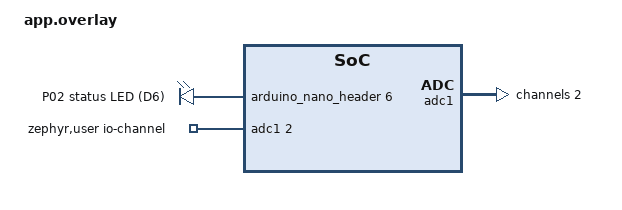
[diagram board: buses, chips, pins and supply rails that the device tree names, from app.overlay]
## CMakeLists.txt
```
# P02 on Zephyr – the Arduino Nano ESP32.

cmake_minimum_required(VERSION 3.20.0)

# Our board definition lives in this repository (zephyr/boards/arduino/nano_esp32).
list(APPEND BOARD_ROOT ${CMAKE_CURRENT_SOURCE_DIR}/..)

find_package(Zephyr REQUIRED HINTS $ENV{ZEPHYR_BASE})
project(p02_zephyr)

# P02's shared code: interfaces, stubs and drivers live in main/ (shared with the ESP-IDF build).
set(P02_MAIN ${CMAKE_CURRENT_SOURCE_DIR}/../../main)
target_include_directories(app PRIVATE ${P02_MAIN}/include)

target_sources(app PRIVATE
    src/main.cpp
    ${P02_MAIN}/source/driver/timer/zephyr.cpp
    ${P02_MAIN}/source/driver/gpio/zephyr.cpp
    ${P02_MAIN}/source/driver/adc/zephyr.cpp
    ${P02_MAIN}/source/driver/serial/zephyr.cpp
    ${P02_MAIN}/source/driver/tempsensor/tmp36.cpp
    ${P02_MAIN}/source/driver/factory/zephyr.cpp
    ${P02_MAIN}/source/driver/nvs/zephyr.cpp
    ${P02_MAIN}/source/driver/watchdog/zephyr.cpp
    ${P02_MAIN}/source/logic/logic.cpp
)
```

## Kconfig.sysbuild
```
# Sysbuild settings for P02 that depend on the board. Settings for every board are in sysbuild.conf.
#
# A Kconfig.sysbuild in the app directory replaces sysbuild's Kconfig root, so the file ends by sourcing
# it. The defaults below come first on purpose: Kconfig uses the first default of a choice whose condition
# is true, and Zephyr's own defaults (swap using offset; overwrite only on Espressif chips) are in the
# sourced files.

# The MCUboot mode: one that can roll an update back. Swap using move works with equal slots, as on these
# boards. The Daisy Seed is not listed: its board keeps RAM load (zephyr/boards/electrosmith/daisy_seed/
# Kconfig.sysbuild).
choice MCUBOOT_MODE
	default MCUBOOT_MODE_SWAP_USING_MOVE if BOARD_NUCLEO_G0B1RE
	default MCUBOOT_MODE_SWAP_USING_MOVE if BOARD_ARDUINO_NANO_ESP32
endchoice

source "share/sysbuild/Kconfig"
```

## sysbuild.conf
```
# P02 on Zephyr boots through MCUboot on every board (build with --sysbuild).
# No signature yet, only a hash check; this also overrides the Daisy board's own default.
# The MCUboot mode is left to each board: setting it here would override the Daisy's RAM load
# (see AGENTS.md: Bootloader).
SB_CONFIG_BOOTLOADER_MCUBOOT=y
SB_CONFIG_BOOT_SIGNATURE_TYPE_NONE=y
```

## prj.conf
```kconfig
# C++17 with the full standard library
CONFIG_CPP=y
CONFIG_STD_CPP17=y
CONFIG_REQUIRES_FULL_LIBCPP=y

# Wait 1 s before booting, so the monitor can open the USB console (re-attached by usbipd after the
# reset) before the boot output is printed.
CONFIG_BOOT_DELAY=1000

# std::this_thread::sleep_for in Logic::step() needs POSIX functions from libstdc++ (usleep, sleep,
# gettimeofday); without this the link fails.
CONFIG_POSIX_API=y

# Logic runs in the main thread, including `store` (Settings -> NVS -> flash driver). Zephyr's default
# of 1 KB is too small for that (see AGENTS.md: Main stack).
CONFIG_MAIN_STACK_SIZE=4096

CONFIG_ADC=y

# serial::Zephyr reads DTR to see when a monitor opens the port, and then drops the input received
# before (on a USB serial port, CDC ACM; other UARTs report "not supported" and nothing changes).
CONFIG_UART_LINE_CTRL=y

# serial::Zephyr receives by interrupt into a ring buffer, so bytes arriving between two readLine()
# calls are kept.
CONFIG_UART_INTERRUPT_DRIVEN=y
CONFIG_RING_BUFFER=y

# nvs::Zephyr: the Settings subsystem stores its keys in storage_partition with the NVS backend.
CONFIG_FLASH=y
CONFIG_FLASH_MAP=y
CONFIG_NVS=y
CONFIG_SETTINGS=y

# Watchdog (driver::watchdog::Zephyr) and the reset cause (hwinfo) for causedLastReset().
CONFIG_WATCHDOG=y
CONFIG_HWINFO=y
```

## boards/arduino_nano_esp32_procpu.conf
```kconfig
# Turns the interrupt API off, so serial::Zephyr polls with uart_poll_in(): receive by interrupt
# does not work on the Nano's USB-Serial/JTAG.
CONFIG_UART_INTERRUPT_DRIVEN=n
```

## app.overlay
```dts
/*
 * P02 wiring on the breadboard for the Zephyr app.
 *
 * Status LED on D6 (GPIO9): D6 -> 330 ohm -> LED anode, LED cathode -> GND.
 * The pin drives the LED directly, so it is active high.
 *
 * TMP36 temperature sensor on A6 (GPIO13 = ADC2 channel 2): Vout -> A6, Vs -> 3V3, GND -> GND.
 * Note: ADC2 cannot be used while Wi-Fi is active - move the TMP36 to A0-A3 (ADC1) when Wi-Fi
 * is added.
 *
 * Only P02's own wiring belongs here. The LEDs on the board itself (led0-led3) are defined by the
 * board (zephyr/boards/arduino/nano_esp32/arduino_nano_esp32_procpu.dts).
 */

#include <zephyr/dt-bindings/gpio/gpio.h>

/ {
	aliases {
		p02-led = &p02_led;
	};

	p02-leds {
		compatible = "gpio-leds";

		p02_led: led-d6 {
			gpios = <&arduino_nano_header 6 GPIO_ACTIVE_HIGH>; /* D6 */
			label = "P02 status LED (D6)";
		};
	};

	zephyr,user {
		io-channels = <&adc1 2>; /* adc1 = the chip's ADC2, channel 2 = GPIO13 = A6 */
	};
};

&adc1 {
	status = "okay";
	#address-cells = <1>;
	#size-cells = <0>;

	/* A6: 12dB attentuation (ADC_GAIN_1_4), range up to ~3.1 V - enough for TMP36 */
	channel@2 {
		reg = <2>;
		zephyr,gain = "ADC_GAIN_1_4";
		zephyr,reference = "ADC_REF_INTERNAL";
		zephyr,acquisition-time = <ADC_ACQ_TIME_DEFAULT>;
		zephyr,resolution = <12>;
	};
};
```

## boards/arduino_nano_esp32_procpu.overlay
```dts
/*
 * P02 wiring on the breadboard for the Zephyr app – Arduino Nano ESP32.
 *
 * Status LED on D6 (GPIO9): D6 -> 330 ohm -> LED anode, LED cathode -> GND.
 * The pin drives the LED directly, so it is active high.
 *
 * TMP36 temperature sensor on A6 (GPIO13 = ADC2 channel 2): Vout -> A6, Vs -> 3V3, GND -> GND.
 * Note: ADC2 cannot be used while Wi-Fi is active - move the TMP36 to A0-A3 (ADC1) when Wi-Fi
 * is added.
 *
 * Only P02's own wiring belongs here. The LEDs on the board itself (led0-led3) are defined by the
 * board (zephyr/boards/arduino/nano_esp32/arduino_nano_esp32_procpu.dts).  
 */

#include <zephyr/dt-bindings/gpio/gpio.h>

/ {
	aliases {
		p02-led = &p02_led;
	};

	p02-leds {
		compatible = "gpio-leds";

		p02_led: led-d6 {
			gpios = <&arduino_nano_header 6 GPIO_ACTIVE_HIGH>; /* D6 */
			label = "P02 status LED (D6)";
		};
	};

	zephyr,user {
		io-channels = <&adc1 2>; /* adc1 = the chip's ADC2, channel 2 = GPIO13 = A6 */
	};
};

&adc1 {
	status = "okay";
	#address-cells = <1>;
	#size-cells = <0>;

	/* A6: 12dB attentuation (ADC_GAIN_1_4), range up to ~3.1 V - enough for TMP36 */
	channel@2 {
		reg = <2>;
		zephyr,gain = "ADC_GAIN_1_4";
		zephyr,reference = "ADC_REF_INTERNAL";
		zephyr,acquisition-time = <ADC_ACQ_TIME_DEFAULT>;
		zephyr,resolution = <12>;
	};
};
```

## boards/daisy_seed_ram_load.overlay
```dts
/*
 * P02 wiring on the breadboard for the Zephyr app – Electrosmith Daisy Seed.
 *
 * Status LED on D26 = pin 33 = PD11: D26 -> 330 ohm -> LED anode, LED cathode -> GND (pin 40).
 * The pin drives the LED directly, so it is active high.
 *
 * TempSensor, simulated by a potentiometer: the wiper -> A3/D18 = pin 25 = PA7 (ADC1 channel 7), the
 * outer legs -> 3V3 (pin 38) and GND (pin 40). P02 converts the voltage with the TMP36 formula.
 *
 * Pins 16 and 20-24 are used by another project on the same breadboard.
 *
 * Only P02's own wiring belongs here. The LED on the board itself (led0) is defined by the board
 * (zephyr/boards/electrosmith/daisy_seed/daisy_seed-common.dtsi).
 */

#include <zephyr/dt-bindings/adc/adc.h>
#include <zephyr/dt-bindings/gpio/gpio.h>

/ {
	aliases {
		p02-led = &p02_led;
	};

	p02-leds {
		compatible = "gpio-leds";

		p02_led: led-d26 {
			gpios = <&daisy_seed_header DAISY_SEED_HEADER_D26 GPIO_ACTIVE_HIGH>; /* D26 = pin 33 = PD11 */
			label = "P02 status LED (D26)";
		};
	};

	zephyr,user {
		io-channels = <&adc1 7>; /* A3/D18 = pin 25 = PA7 = ADC1 channel 7 */
	};
};

&adc1 {
	pinctrl-0 = <&adc1_inp7_pa7>;
	pinctrl-names = "default";
	st,adc-clock-source = "SYNC";
	st,adc-prescaler = <4>;
	status = "okay";
	#address-cells = <1>;
	#size-cells = <0>;

	/* A3: full range 0-3.3 V (the ADC's reference is the Daisy's 3V3). */
	channel@7 {
		reg = <7>;
		zephyr,gain = "ADC_GAIN_1";
		zephyr,reference = "ADC_REF_INTERNAL";
		zephyr,acquisition-time = <ADC_ACQ_TIME(ADC_ACQ_TIME_TICKS, 65)>;
		zephyr,resolution = <12>;
	};
};
```

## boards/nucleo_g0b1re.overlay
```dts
/*
 * P02 wiring for the Zephyr app – ST Nucleo-G0B1RE.
 *
 * Status LED on D6 = PB14 (Arduino header): D6 -> 330 ohm -> LED anode, LED cathode -> GND.
 * The pin drives the LED directly, so it is active high.
 *
 * TMP36 temperature sensor on A0 = PA0 (ADC1 channel 0): Vout -> A0, Vs -> 3V3, GND -> GND (all three on
 * the Arduino header). With the flat side facing you, the TMP36's pins are Vs, Vout, GND.
 *
 * Only P02's own wiring belongs here. The LED on the board itself (led0 = LD4 on PA5) is defined by
 * the board (Zephyr's boards/st/nucleo_g0b1re), which also enables adc1 with PA0 in its pinctrl.
 */

#include <zephyr/dt-bindings/adc/adc.h>
#include <zephyr/dt-bindings/gpio/gpio.h>

/ {
	aliases {
		p02-led = &p02_led;
	};

	p02-leds {
		compatible = "gpio-leds";

		p02_led: led-d6 {
			gpios = <&arduino_header ARDUINO_HEADER_R3_D6 GPIO_ACTIVE_HIGH>; /* D6 = PB14 */
			label = "P02 status LED (D6)";
		};
	};

	zephyr,user {
		io-channels = <&adc1 0>; /* A0 = PA0 = ADC1 channel 0 */
	};
};

&adc1 {
	#address-cells = <1>;
	#size-cells = <0>;

	/* A0: full range 0-3.3 V (the ADC's reference is VREF+, tied to 3V3 on the Nucleo). */
	channel@0 {
		reg = <0>;
		zephyr,gain = "ADC_GAIN_1";
		zephyr,reference = "ADC_REF_INTERNAL";
		zephyr,acquisition-time = <ADC_ACQ_TIME_DEFAULT>;
		zephyr,resolution = <12>;
	};
};
```

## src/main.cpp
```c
/**
 * @file P02 on Zephyr: application entry point.
 */

#include "driver/factory/zephyr.h"
#include "logic/logic.h"

int main()
{
    // The Zephyr build uses the Zephyr drivers.
    driver::factory::Zephyr factory{};
    logic::Logic logic{factory};
    logic.run();
    return 0;
}
```
